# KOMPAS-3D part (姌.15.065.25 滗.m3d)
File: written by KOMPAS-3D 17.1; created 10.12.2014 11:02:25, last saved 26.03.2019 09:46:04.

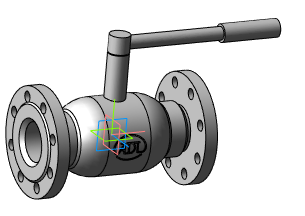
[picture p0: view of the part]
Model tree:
1. Операция без истории:4  (labels: Сталь 20  ГОСТ 1050-88)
